VERSION 5.7 ;
  NOWIREEXTENSIONATPIN ON ;
  DIVIDERCHAR "/" ;
  BUSBITCHARS "[]" ;
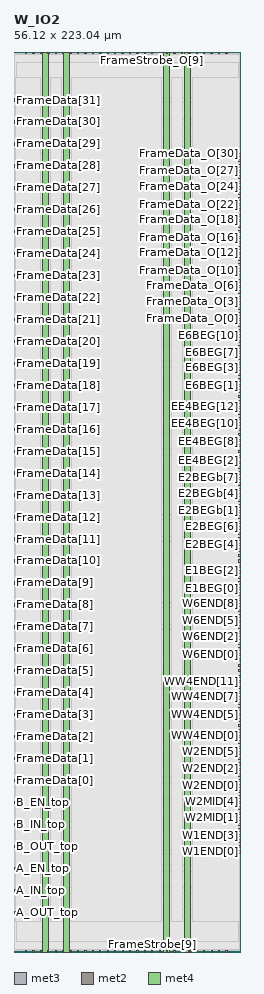
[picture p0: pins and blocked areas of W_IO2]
MACRO W_IO2
  CLASS BLOCK ;
  FOREIGN W_IO2 ;
  ORIGIN 0.000 0.000 ;
  SIZE 56.120 BY 223.040 ;
  PIN A_EN_top
    DIRECTION OUTPUT ;
    USE SIGNAL ;
    ANTENNADIFFAREA 0.702900 ;
    PORT
      LAYER met3 ;
        RECT 0.000 20.440 0.600 21.040 ;
    END
  END A_EN_top
  PIN A_IN_top
    DIRECTION OUTPUT ;
    USE SIGNAL ;
    ANTENNADIFFAREA 0.702900 ;
    PORT
      LAYER met3 ;
        RECT 0.000 15.000 0.600 15.600 ;
    END
  END A_IN_top
  PIN A_OUT_top
    DIRECTION INPUT ;
    USE SIGNAL ;
    ANTENNAGATEAREA 0.252000 ;
    PORT
      LAYER met3 ;
        RECT 0.000 9.560 0.600 10.160 ;
    END
  END A_OUT_top
  PIN B_EN_top
    DIRECTION OUTPUT ;
    USE SIGNAL ;
    ANTENNADIFFAREA 0.702900 ;
    PORT
      LAYER met3 ;
        RECT 0.000 36.760 0.600 37.360 ;
    END
  END B_EN_top
  PIN B_IN_top
    DIRECTION OUTPUT ;
    USE SIGNAL ;
    ANTENNADIFFAREA 0.702900 ;
    PORT
      LAYER met3 ;
        RECT 0.000 31.320 0.600 31.920 ;
    END
  END B_IN_top
  PIN B_OUT_top
    DIRECTION INPUT ;
    USE SIGNAL ;
    ANTENNAGATEAREA 0.252000 ;
    PORT
      LAYER met3 ;
        RECT 0.000 25.880 0.600 26.480 ;
    END
  END B_OUT_top
  PIN E1BEG[0]
    DIRECTION OUTPUT ;
    USE SIGNAL ;
    ANTENNADIFFAREA 0.702900 ;
    PORT
      LAYER met3 ;
        RECT 55.520 89.800 56.120 90.400 ;
    END
  END E1BEG[0]
  PIN E1BEG[1]
    DIRECTION OUTPUT ;
    USE SIGNAL ;
    ANTENNADIFFAREA 0.702900 ;
    PORT
      LAYER met3 ;
        RECT 55.520 91.160 56.120 91.760 ;
    END
  END E1BEG[1]
  PIN E1BEG[2]
    DIRECTION OUTPUT ;
    USE SIGNAL ;
    ANTENNADIFFAREA 0.702900 ;
    PORT
      LAYER met3 ;
        RECT 55.520 92.520 56.120 93.120 ;
    END
  END E1BEG[2]
  PIN E1BEG[3]
    DIRECTION OUTPUT ;
    USE SIGNAL ;
    ANTENNADIFFAREA 0.702900 ;
    PORT
      LAYER met3 ;
        RECT 55.520 93.880 56.120 94.480 ;
    END
  END E1BEG[3]
  PIN E2BEG[0]
    DIRECTION OUTPUT ;
    USE SIGNAL ;
    ANTENNADIFFAREA 0.702900 ;
    PORT
      LAYER met3 ;
        RECT 55.520 95.240 56.120 95.840 ;
    END
  END E2BEG[0]
  PIN E2BEG[1]
    DIRECTION OUTPUT ;
    USE SIGNAL ;
    ANTENNADIFFAREA 0.702900 ;
    PORT
      LAYER met3 ;
        RECT 55.520 96.600 56.120 97.200 ;
    END
  END E2BEG[1]
  PIN E2BEG[2]
    DIRECTION OUTPUT ;
    USE SIGNAL ;
    ANTENNADIFFAREA 0.702900 ;
    PORT
      LAYER met3 ;
        RECT 55.520 97.960 56.120 98.560 ;
    END
  END E2BEG[2]
  PIN E2BEG[3]
    DIRECTION OUTPUT ;
    USE SIGNAL ;
    ANTENNADIFFAREA 0.702900 ;
    PORT
      LAYER met3 ;
        RECT 55.520 99.320 56.120 99.920 ;
    END
  END E2BEG[3]
  PIN E2BEG[4]
    DIRECTION OUTPUT ;
    USE SIGNAL ;
    ANTENNADIFFAREA 0.702900 ;
    PORT
      LAYER met3 ;
        RECT 55.520 100.680 56.120 101.280 ;
    END
  END E2BEG[4]
  PIN E2BEG[5]
    DIRECTION OUTPUT ;
    USE SIGNAL ;
    ANTENNADIFFAREA 0.702900 ;
    PORT
      LAYER met3 ;
        RECT 55.520 102.040 56.120 102.640 ;
    END
  END E2BEG[5]
  PIN E2BEG[6]
    DIRECTION OUTPUT ;
    USE SIGNAL ;
    ANTENNADIFFAREA 0.702900 ;
    PORT
      LAYER met3 ;
        RECT 55.520 103.400 56.120 104.000 ;
    END
  END E2BEG[6]
  PIN E2BEG[7]
    DIRECTION OUTPUT ;
    USE SIGNAL ;
    ANTENNADIFFAREA 0.702900 ;
    PORT
      LAYER met3 ;
        RECT 55.520 104.760 56.120 105.360 ;
    END
  END E2BEG[7]
  PIN E2BEGb[0]
    DIRECTION OUTPUT ;
    USE SIGNAL ;
    ANTENNADIFFAREA 0.702900 ;
    PORT
      LAYER met3 ;
        RECT 55.520 106.120 56.120 106.720 ;
    END
  END E2BEGb[0]
  PIN E2BEGb[1]
    DIRECTION OUTPUT ;
    USE SIGNAL ;
    ANTENNADIFFAREA 0.702900 ;
    PORT
      LAYER met3 ;
        RECT 55.520 107.480 56.120 108.080 ;
    END
  END E2BEGb[1]
  PIN E2BEGb[2]
    DIRECTION OUTPUT ;
    USE SIGNAL ;
    ANTENNADIFFAREA 0.702900 ;
    PORT
      LAYER met3 ;
        RECT 55.520 108.840 56.120 109.440 ;
    END
  END E2BEGb[2]
  PIN E2BEGb[3]
    DIRECTION OUTPUT ;
    USE SIGNAL ;
    ANTENNADIFFAREA 0.702900 ;
    PORT
      LAYER met3 ;
        RECT 55.520 110.200 56.120 110.800 ;
    END
  END E2BEGb[3]
  PIN E2BEGb[4]
    DIRECTION OUTPUT ;
    USE SIGNAL ;
    ANTENNADIFFAREA 0.702900 ;
    PORT
      LAYER met3 ;
        RECT 55.520 111.560 56.120 112.160 ;
    END
  END E2BEGb[4]
  PIN E2BEGb[5]
    DIRECTION OUTPUT ;
    USE SIGNAL ;
    ANTENNADIFFAREA 0.702900 ;
    PORT
      LAYER met3 ;
        RECT 55.520 112.920 56.120 113.520 ;
    END
  END E2BEGb[5]
  PIN E2BEGb[6]
    DIRECTION OUTPUT ;
    USE SIGNAL ;
    ANTENNADIFFAREA 0.702900 ;
    PORT
      LAYER met3 ;
        RECT 55.520 114.280 56.120 114.880 ;
    END
  END E2BEGb[6]
  PIN E2BEGb[7]
    DIRECTION OUTPUT ;
    USE SIGNAL ;
    ANTENNADIFFAREA 0.702900 ;
    PORT
      LAYER met3 ;
        RECT 55.520 115.640 56.120 116.240 ;
    END
  END E2BEGb[7]
  PIN E6BEG[0]
    DIRECTION OUTPUT ;
    USE SIGNAL ;
    ANTENNADIFFAREA 0.702900 ;
    PORT
      LAYER met3 ;
        RECT 55.520 138.760 56.120 139.360 ;
    END
  END E6BEG[0]
  PIN E6BEG[10]
    DIRECTION OUTPUT ;
    USE SIGNAL ;
    ANTENNADIFFAREA 0.702900 ;
    PORT
      LAYER met3 ;
        RECT 55.520 152.360 56.120 152.960 ;
    END
  END E6BEG[10]
  PIN E6BEG[11]
    DIRECTION OUTPUT ;
    USE SIGNAL ;
    ANTENNADIFFAREA 0.702900 ;
    PORT
      LAYER met3 ;
        RECT 55.520 153.720 56.120 154.320 ;
    END
  END E6BEG[11]
  PIN E6BEG[1]
    DIRECTION OUTPUT ;
    USE SIGNAL ;
    ANTENNADIFFAREA 0.702900 ;
    PORT
      LAYER met3 ;
        RECT 55.520 140.120 56.120 140.720 ;
    END
  END E6BEG[1]
  PIN E6BEG[2]
    DIRECTION OUTPUT ;
    USE SIGNAL ;
    ANTENNADIFFAREA 0.702900 ;
    PORT
      LAYER met3 ;
        RECT 55.520 141.480 56.120 142.080 ;
    END
  END E6BEG[2]
  PIN E6BEG[3]
    DIRECTION OUTPUT ;
    USE SIGNAL ;
    ANTENNADIFFAREA 0.702900 ;
    PORT
      LAYER met3 ;
        RECT 55.520 142.840 56.120 143.440 ;
    END
  END E6BEG[3]
  PIN E6BEG[4]
    DIRECTION OUTPUT ;
    USE SIGNAL ;
    ANTENNADIFFAREA 0.702900 ;
    PORT
      LAYER met3 ;
        RECT 55.520 144.200 56.120 144.800 ;
    END
  END E6BEG[4]
  PIN E6BEG[5]
    DIRECTION OUTPUT ;
    USE SIGNAL ;
    ANTENNADIFFAREA 0.702900 ;
    PORT
      LAYER met3 ;
        RECT 55.520 145.560 56.120 146.160 ;
    END
  END E6BEG[5]
  PIN E6BEG[6]
    DIRECTION OUTPUT ;
    USE SIGNAL ;
    ANTENNADIFFAREA 0.702900 ;
    PORT
      LAYER met3 ;
        RECT 55.520 146.920 56.120 147.520 ;
    END
  END E6BEG[6]
  PIN E6BEG[7]
    DIRECTION OUTPUT ;
    USE SIGNAL ;
    ANTENNADIFFAREA 0.702900 ;
    PORT
      LAYER met3 ;
        RECT 55.520 148.280 56.120 148.880 ;
    END
  END E6BEG[7]
  PIN E6BEG[8]
    DIRECTION OUTPUT ;
    USE SIGNAL ;
    ANTENNADIFFAREA 0.702900 ;
    PORT
      LAYER met3 ;
        RECT 55.520 149.640 56.120 150.240 ;
    END
  END E6BEG[8]
  PIN E6BEG[9]
    DIRECTION OUTPUT ;
    USE SIGNAL ;
    ANTENNADIFFAREA 0.702900 ;
    PORT
      LAYER met3 ;
        RECT 55.520 151.000 56.120 151.600 ;
    END
  END E6BEG[9]
  PIN EE4BEG[0]
    DIRECTION OUTPUT ;
    USE SIGNAL ;
    ANTENNADIFFAREA 0.702900 ;
    PORT
      LAYER met3 ;
        RECT 55.520 117.000 56.120 117.600 ;
    END
  END EE4BEG[0]
  PIN EE4BEG[10]
    DIRECTION OUTPUT ;
    USE SIGNAL ;
    ANTENNADIFFAREA 0.702900 ;
    PORT
      LAYER met3 ;
        RECT 55.520 130.600 56.120 131.200 ;
    END
  END EE4BEG[10]
  PIN EE4BEG[11]
    DIRECTION OUTPUT ;
    USE SIGNAL ;
    ANTENNADIFFAREA 0.702900 ;
    PORT
      LAYER met3 ;
        RECT 55.520 131.960 56.120 132.560 ;
    END
  END EE4BEG[11]
  PIN EE4BEG[12]
    DIRECTION OUTPUT ;
    USE SIGNAL ;
    ANTENNADIFFAREA 0.702900 ;
    PORT
      LAYER met3 ;
        RECT 55.520 133.320 56.120 133.920 ;
    END
  END EE4BEG[12]
  PIN EE4BEG[13]
    DIRECTION OUTPUT ;
    USE SIGNAL ;
    ANTENNADIFFAREA 0.702900 ;
    PORT
      LAYER met3 ;
        RECT 55.520 134.680 56.120 135.280 ;
    END
  END EE4BEG[13]
  PIN EE4BEG[14]
    DIRECTION OUTPUT ;
    USE SIGNAL ;
    ANTENNADIFFAREA 0.702900 ;
    PORT
      LAYER met3 ;
        RECT 55.520 136.040 56.120 136.640 ;
    END
  END EE4BEG[14]
  PIN EE4BEG[15]
    DIRECTION OUTPUT ;
    USE SIGNAL ;
    ANTENNADIFFAREA 0.702900 ;
    PORT
      LAYER met3 ;
        RECT 55.520 137.400 56.120 138.000 ;
    END
  END EE4BEG[15]
  PIN EE4BEG[1]
    DIRECTION OUTPUT ;
    USE SIGNAL ;
    ANTENNADIFFAREA 0.702900 ;
    PORT
      LAYER met3 ;
        RECT 55.520 118.360 56.120 118.960 ;
    END
  END EE4BEG[1]
  PIN EE4BEG[2]
    DIRECTION OUTPUT ;
    USE SIGNAL ;
    ANTENNADIFFAREA 0.702900 ;
    PORT
      LAYER met3 ;
        RECT 55.520 119.720 56.120 120.320 ;
    END
  END EE4BEG[2]
  PIN EE4BEG[3]
    DIRECTION OUTPUT ;
    USE SIGNAL ;
    ANTENNADIFFAREA 0.702900 ;
    PORT
      LAYER met3 ;
        RECT 55.520 121.080 56.120 121.680 ;
    END
  END EE4BEG[3]
  PIN EE4BEG[4]
    DIRECTION OUTPUT ;
    USE SIGNAL ;
    ANTENNADIFFAREA 0.702900 ;
    PORT
      LAYER met3 ;
        RECT 55.520 122.440 56.120 123.040 ;
    END
  END EE4BEG[4]
  PIN EE4BEG[5]
    DIRECTION OUTPUT ;
    USE SIGNAL ;
    ANTENNADIFFAREA 0.702900 ;
    PORT
      LAYER met3 ;
        RECT 55.520 123.800 56.120 124.400 ;
    END
  END EE4BEG[5]
  PIN EE4BEG[6]
    DIRECTION OUTPUT ;
    USE SIGNAL ;
    ANTENNADIFFAREA 0.702900 ;
    PORT
      LAYER met3 ;
        RECT 55.520 125.160 56.120 125.760 ;
    END
  END EE4BEG[6]
  PIN EE4BEG[7]
    DIRECTION OUTPUT ;
    USE SIGNAL ;
    ANTENNADIFFAREA 0.702900 ;
    PORT
      LAYER met3 ;
        RECT 55.520 126.520 56.120 127.120 ;
    END
  END EE4BEG[7]
  PIN EE4BEG[8]
    DIRECTION OUTPUT ;
    USE SIGNAL ;
    ANTENNADIFFAREA 0.702900 ;
    PORT
      LAYER met3 ;
        RECT 55.520 127.880 56.120 128.480 ;
    END
  END EE4BEG[8]
  PIN EE4BEG[9]
    DIRECTION OUTPUT ;
    USE SIGNAL ;
    ANTENNADIFFAREA 0.702900 ;
    PORT
      LAYER met3 ;
        RECT 55.520 129.240 56.120 129.840 ;
    END
  END EE4BEG[9]
  PIN FrameData[0]
    DIRECTION INPUT ;
    USE SIGNAL ;
    ANTENNAGATEAREA 0.636000 ;
    PORT
      LAYER met3 ;
        RECT 0.000 42.200 0.600 42.800 ;
    END
  END FrameData[0]
  PIN FrameData[10]
    DIRECTION INPUT ;
    USE SIGNAL ;
    ANTENNAGATEAREA 0.795000 ;
    PORT
      LAYER met3 ;
        RECT 0.000 96.600 0.600 97.200 ;
    END
  END FrameData[10]
  PIN FrameData[11]
    DIRECTION INPUT ;
    USE SIGNAL ;
    ANTENNAGATEAREA 0.795000 ;
    PORT
      LAYER met3 ;
        RECT 0.000 102.040 0.600 102.640 ;
    END
  END FrameData[11]
  PIN FrameData[12]
    DIRECTION INPUT ;
    USE SIGNAL ;
    ANTENNAGATEAREA 0.795000 ;
    PORT
      LAYER met3 ;
        RECT 0.000 107.480 0.600 108.080 ;
    END
  END FrameData[12]
  PIN FrameData[13]
    DIRECTION INPUT ;
    USE SIGNAL ;
    ANTENNAGATEAREA 0.795000 ;
    PORT
      LAYER met3 ;
        RECT 0.000 112.920 0.600 113.520 ;
    END
  END FrameData[13]
  PIN FrameData[14]
    DIRECTION INPUT ;
    USE SIGNAL ;
    ANTENNAGATEAREA 0.795000 ;
    PORT
      LAYER met3 ;
        RECT 0.000 118.360 0.600 118.960 ;
    END
  END FrameData[14]
  PIN FrameData[15]
    DIRECTION INPUT ;
    USE SIGNAL ;
    ANTENNAGATEAREA 0.795000 ;
    PORT
      LAYER met3 ;
        RECT 0.000 123.800 0.600 124.400 ;
    END
  END FrameData[15]
  PIN FrameData[16]
    DIRECTION INPUT ;
    USE SIGNAL ;
    ANTENNAGATEAREA 0.795000 ;
    PORT
      LAYER met3 ;
        RECT 0.000 129.240 0.600 129.840 ;
    END
  END FrameData[16]
  PIN FrameData[17]
    DIRECTION INPUT ;
    USE SIGNAL ;
    ANTENNAGATEAREA 0.795000 ;
    PORT
      LAYER met3 ;
        RECT 0.000 134.680 0.600 135.280 ;
    END
  END FrameData[17]
  PIN FrameData[18]
    DIRECTION INPUT ;
    USE SIGNAL ;
    ANTENNAGATEAREA 1.229700 ;
    ANTENNADIFFAREA 0.434700 ;
    PORT
      LAYER met3 ;
        RECT 0.000 140.120 0.600 140.720 ;
    END
  END FrameData[18]
  PIN FrameData[19]
    DIRECTION INPUT ;
    USE SIGNAL ;
    ANTENNAGATEAREA 0.795000 ;
    PORT
      LAYER met3 ;
        RECT 0.000 145.560 0.600 146.160 ;
    END
  END FrameData[19]
  PIN FrameData[1]
    DIRECTION INPUT ;
    USE SIGNAL ;
    ANTENNAGATEAREA 0.636000 ;
    PORT
      LAYER met3 ;
        RECT 0.000 47.640 0.600 48.240 ;
    END
  END FrameData[1]
  PIN FrameData[20]
    DIRECTION INPUT ;
    USE SIGNAL ;
    ANTENNAGATEAREA 0.795000 ;
    PORT
      LAYER met3 ;
        RECT 0.000 151.000 0.600 151.600 ;
    END
  END FrameData[20]
  PIN FrameData[21]
    DIRECTION INPUT ;
    USE SIGNAL ;
    ANTENNAGATEAREA 0.795000 ;
    PORT
      LAYER met3 ;
        RECT 0.000 156.440 0.600 157.040 ;
    END
  END FrameData[21]
  PIN FrameData[22]
    DIRECTION INPUT ;
    USE SIGNAL ;
    ANTENNAGATEAREA 1.229700 ;
    ANTENNADIFFAREA 0.434700 ;
    PORT
      LAYER met3 ;
        RECT 0.000 161.880 0.600 162.480 ;
    END
  END FrameData[22]
  PIN FrameData[23]
    DIRECTION INPUT ;
    USE SIGNAL ;
    ANTENNAGATEAREA 0.795000 ;
    PORT
      LAYER met3 ;
        RECT 0.000 167.320 0.600 167.920 ;
    END
  END FrameData[23]
  PIN FrameData[24]
    DIRECTION INPUT ;
    USE SIGNAL ;
    ANTENNAGATEAREA 0.795000 ;
    PORT
      LAYER met3 ;
        RECT 0.000 172.760 0.600 173.360 ;
    END
  END FrameData[24]
  PIN FrameData[25]
    DIRECTION INPUT ;
    USE SIGNAL ;
    ANTENNAGATEAREA 0.795000 ;
    PORT
      LAYER met3 ;
        RECT 0.000 178.200 0.600 178.800 ;
    END
  END FrameData[25]
  PIN FrameData[26]
    DIRECTION INPUT ;
    USE SIGNAL ;
    ANTENNAGATEAREA 0.795000 ;
    PORT
      LAYER met3 ;
        RECT 0.000 183.640 0.600 184.240 ;
    END
  END FrameData[26]
  PIN FrameData[27]
    DIRECTION INPUT ;
    USE SIGNAL ;
    ANTENNAGATEAREA 0.795000 ;
    PORT
      LAYER met3 ;
        RECT 0.000 189.080 0.600 189.680 ;
    END
  END FrameData[27]
  PIN FrameData[28]
    DIRECTION INPUT ;
    USE SIGNAL ;
    ANTENNAGATEAREA 0.795000 ;
    PORT
      LAYER met3 ;
        RECT 0.000 194.520 0.600 195.120 ;
    END
  END FrameData[28]
  PIN FrameData[29]
    DIRECTION INPUT ;
    USE SIGNAL ;
    ANTENNAGATEAREA 0.795000 ;
    PORT
      LAYER met3 ;
        RECT 0.000 199.960 0.600 200.560 ;
    END
  END FrameData[29]
  PIN FrameData[2]
    DIRECTION INPUT ;
    USE SIGNAL ;
    ANTENNAGATEAREA 0.795000 ;
    PORT
      LAYER met3 ;
        RECT 0.000 53.080 0.600 53.680 ;
    END
  END FrameData[2]
  PIN FrameData[30]
    DIRECTION INPUT ;
    USE SIGNAL ;
    ANTENNAGATEAREA 0.795000 ;
    PORT
      LAYER met3 ;
        RECT 0.000 205.400 0.600 206.000 ;
    END
  END FrameData[30]
  PIN FrameData[31]
    DIRECTION INPUT ;
    USE SIGNAL ;
    ANTENNAGATEAREA 0.795000 ;
    PORT
      LAYER met3 ;
        RECT 0.000 210.840 0.600 211.440 ;
    END
  END FrameData[31]
  PIN FrameData[3]
    DIRECTION INPUT ;
    USE SIGNAL ;
    ANTENNAGATEAREA 0.795000 ;
    PORT
      LAYER met3 ;
        RECT 0.000 58.520 0.600 59.120 ;
    END
  END FrameData[3]
  PIN FrameData[4]
    DIRECTION INPUT ;
    USE SIGNAL ;
    ANTENNAGATEAREA 0.795000 ;
    PORT
      LAYER met3 ;
        RECT 0.000 63.960 0.600 64.560 ;
    END
  END FrameData[4]
  PIN FrameData[5]
    DIRECTION INPUT ;
    USE SIGNAL ;
    ANTENNAGATEAREA 0.795000 ;
    PORT
      LAYER met3 ;
        RECT 0.000 69.400 0.600 70.000 ;
    END
  END FrameData[5]
  PIN FrameData[6]
    DIRECTION INPUT ;
    USE SIGNAL ;
    ANTENNAGATEAREA 0.795000 ;
    PORT
      LAYER met3 ;
        RECT 0.000 74.840 0.600 75.440 ;
    END
  END FrameData[6]
  PIN FrameData[7]
    DIRECTION INPUT ;
    USE SIGNAL ;
    ANTENNAGATEAREA 0.795000 ;
    PORT
      LAYER met3 ;
        RECT 0.000 80.280 0.600 80.880 ;
    END
  END FrameData[7]
  PIN FrameData[8]
    DIRECTION INPUT ;
    USE SIGNAL ;
    ANTENNAGATEAREA 0.795000 ;
    PORT
      LAYER met3 ;
        RECT 0.000 85.720 0.600 86.320 ;
    END
  END FrameData[8]
  PIN FrameData[9]
    DIRECTION INPUT ;
    USE SIGNAL ;
    ANTENNAGATEAREA 0.795000 ;
    PORT
      LAYER met3 ;
        RECT 0.000 91.160 0.600 91.760 ;
    END
  END FrameData[9]
  PIN FrameData_O[0]
    DIRECTION OUTPUT ;
    USE SIGNAL ;
    ANTENNADIFFAREA 0.702900 ;
    PORT
      LAYER met3 ;
        RECT 55.520 155.080 56.120 155.680 ;
    END
  END FrameData_O[0]
  PIN FrameData_O[10]
    DIRECTION OUTPUT ;
    USE SIGNAL ;
    ANTENNADIFFAREA 0.702900 ;
    PORT
      LAYER met3 ;
        RECT 55.520 168.680 56.120 169.280 ;
    END
  END FrameData_O[10]
  PIN FrameData_O[11]
    DIRECTION OUTPUT ;
    USE SIGNAL ;
    ANTENNADIFFAREA 0.702900 ;
    PORT
      LAYER met3 ;
        RECT 55.520 170.040 56.120 170.640 ;
    END
  END FrameData_O[11]
  PIN FrameData_O[12]
    DIRECTION OUTPUT ;
    USE SIGNAL ;
    ANTENNADIFFAREA 0.702900 ;
    PORT
      LAYER met3 ;
        RECT 55.520 171.400 56.120 172.000 ;
    END
  END FrameData_O[12]
  PIN FrameData_O[13]
    DIRECTION OUTPUT ;
    USE SIGNAL ;
    ANTENNADIFFAREA 0.702900 ;
    PORT
      LAYER met3 ;
        RECT 55.520 172.760 56.120 173.360 ;
    END
  END FrameData_O[13]
  PIN FrameData_O[14]
    DIRECTION OUTPUT ;
    USE SIGNAL ;
    ANTENNADIFFAREA 0.702900 ;
    PORT
      LAYER met3 ;
        RECT 55.520 174.120 56.120 174.720 ;
    END
  END FrameData_O[14]
  PIN FrameData_O[15]
    DIRECTION OUTPUT ;
    USE SIGNAL ;
    ANTENNADIFFAREA 0.702900 ;
    PORT
      LAYER met3 ;
        RECT 55.520 175.480 56.120 176.080 ;
    END
  END FrameData_O[15]
  PIN FrameData_O[16]
    DIRECTION OUTPUT ;
    USE SIGNAL ;
    ANTENNADIFFAREA 0.702900 ;
    PORT
      LAYER met3 ;
        RECT 55.520 176.840 56.120 177.440 ;
    END
  END FrameData_O[16]
  PIN FrameData_O[17]
    DIRECTION OUTPUT ;
    USE SIGNAL ;
    ANTENNADIFFAREA 0.702900 ;
    PORT
      LAYER met3 ;
        RECT 55.520 178.200 56.120 178.800 ;
    END
  END FrameData_O[17]
  PIN FrameData_O[18]
    DIRECTION OUTPUT ;
    USE SIGNAL ;
    ANTENNADIFFAREA 0.702900 ;
    PORT
      LAYER met3 ;
        RECT 55.520 179.560 56.120 180.160 ;
    END
  END FrameData_O[18]
  PIN FrameData_O[19]
    DIRECTION OUTPUT ;
    USE SIGNAL ;
    ANTENNADIFFAREA 0.702900 ;
    PORT
      LAYER met3 ;
        RECT 55.520 180.920 56.120 181.520 ;
    END
  END FrameData_O[19]
  PIN FrameData_O[1]
    DIRECTION OUTPUT ;
    USE SIGNAL ;
    ANTENNADIFFAREA 0.702900 ;
    PORT
      LAYER met3 ;
        RECT 55.520 156.440 56.120 157.040 ;
    END
  END FrameData_O[1]
  PIN FrameData_O[20]
    DIRECTION OUTPUT ;
    USE SIGNAL ;
    ANTENNADIFFAREA 0.702900 ;
    PORT
      LAYER met3 ;
        RECT 55.520 182.280 56.120 182.880 ;
    END
  END FrameData_O[20]
  PIN FrameData_O[21]
    DIRECTION OUTPUT ;
    USE SIGNAL ;
    ANTENNADIFFAREA 0.702900 ;
    PORT
      LAYER met3 ;
        RECT 55.520 183.640 56.120 184.240 ;
    END
  END FrameData_O[21]
  PIN FrameData_O[22]
    DIRECTION OUTPUT ;
    USE SIGNAL ;
    ANTENNADIFFAREA 0.702900 ;
    PORT
      LAYER met3 ;
        RECT 55.520 185.000 56.120 185.600 ;
    END
  END FrameData_O[22]
  PIN FrameData_O[23]
    DIRECTION OUTPUT ;
    USE SIGNAL ;
    ANTENNADIFFAREA 0.702900 ;
    PORT
      LAYER met3 ;
        RECT 55.520 186.360 56.120 186.960 ;
    END
  END FrameData_O[23]
  PIN FrameData_O[24]
    DIRECTION OUTPUT ;
    USE SIGNAL ;
    ANTENNADIFFAREA 0.702900 ;
    PORT
      LAYER met3 ;
        RECT 55.520 187.720 56.120 188.320 ;
    END
  END FrameData_O[24]
  PIN FrameData_O[25]
    DIRECTION OUTPUT ;
    USE SIGNAL ;
    ANTENNADIFFAREA 0.702900 ;
    PORT
      LAYER met3 ;
        RECT 55.520 189.080 56.120 189.680 ;
    END
  END FrameData_O[25]
  PIN FrameData_O[26]
    DIRECTION OUTPUT ;
    USE SIGNAL ;
    ANTENNADIFFAREA 0.702900 ;
    PORT
      LAYER met3 ;
        RECT 55.520 190.440 56.120 191.040 ;
    END
  END FrameData_O[26]
  PIN FrameData_O[27]
    DIRECTION OUTPUT ;
    USE SIGNAL ;
    ANTENNADIFFAREA 0.702900 ;
    PORT
      LAYER met3 ;
        RECT 55.520 191.800 56.120 192.400 ;
    END
  END FrameData_O[27]
  PIN FrameData_O[28]
    DIRECTION OUTPUT ;
    USE SIGNAL ;
    ANTENNADIFFAREA 0.702900 ;
    PORT
      LAYER met3 ;
        RECT 55.520 193.160 56.120 193.760 ;
    END
  END FrameData_O[28]
  PIN FrameData_O[29]
    DIRECTION OUTPUT ;
    USE SIGNAL ;
    ANTENNADIFFAREA 0.702900 ;
    PORT
      LAYER met3 ;
        RECT 55.520 194.520 56.120 195.120 ;
    END
  END FrameData_O[29]
  PIN FrameData_O[2]
    DIRECTION OUTPUT ;
    USE SIGNAL ;
    ANTENNADIFFAREA 0.702900 ;
    PORT
      LAYER met3 ;
        RECT 55.520 157.800 56.120 158.400 ;
    END
  END FrameData_O[2]
  PIN FrameData_O[30]
    DIRECTION OUTPUT ;
    USE SIGNAL ;
    ANTENNADIFFAREA 0.702900 ;
    PORT
      LAYER met3 ;
        RECT 55.520 195.880 56.120 196.480 ;
    END
  END FrameData_O[30]
  PIN FrameData_O[31]
    DIRECTION OUTPUT ;
    USE SIGNAL ;
    ANTENNADIFFAREA 0.702900 ;
    PORT
      LAYER met3 ;
        RECT 55.520 197.240 56.120 197.840 ;
    END
  END FrameData_O[31]
  PIN FrameData_O[3]
    DIRECTION OUTPUT ;
    USE SIGNAL ;
    ANTENNADIFFAREA 0.702900 ;
    PORT
      LAYER met3 ;
        RECT 55.520 159.160 56.120 159.760 ;
    END
  END FrameData_O[3]
  PIN FrameData_O[4]
    DIRECTION OUTPUT ;
    USE SIGNAL ;
    ANTENNADIFFAREA 0.702900 ;
    PORT
      LAYER met3 ;
        RECT 55.520 160.520 56.120 161.120 ;
    END
  END FrameData_O[4]
  PIN FrameData_O[5]
    DIRECTION OUTPUT ;
    USE SIGNAL ;
    ANTENNADIFFAREA 0.702900 ;
    PORT
      LAYER met3 ;
        RECT 55.520 161.880 56.120 162.480 ;
    END
  END FrameData_O[5]
  PIN FrameData_O[6]
    DIRECTION OUTPUT ;
    USE SIGNAL ;
    ANTENNADIFFAREA 0.702900 ;
    PORT
      LAYER met3 ;
        RECT 55.520 163.240 56.120 163.840 ;
    END
  END FrameData_O[6]
  PIN FrameData_O[7]
    DIRECTION OUTPUT ;
    USE SIGNAL ;
    ANTENNADIFFAREA 0.702900 ;
    PORT
      LAYER met3 ;
        RECT 55.520 164.600 56.120 165.200 ;
    END
  END FrameData_O[7]
  PIN FrameData_O[8]
    DIRECTION OUTPUT ;
    USE SIGNAL ;
    ANTENNADIFFAREA 0.702900 ;
    PORT
      LAYER met3 ;
        RECT 55.520 165.960 56.120 166.560 ;
    END
  END FrameData_O[8]
  PIN FrameData_O[9]
    DIRECTION OUTPUT ;
    USE SIGNAL ;
    ANTENNADIFFAREA 0.702900 ;
    PORT
      LAYER met3 ;
        RECT 55.520 167.320 56.120 167.920 ;
    END
  END FrameData_O[9]
  PIN FrameStrobe[0]
    DIRECTION INPUT ;
    USE SIGNAL ;
    ANTENNAGATEAREA 5.247000 ;
    PORT
      LAYER met2 ;
        RECT 17.570 0.000 17.850 0.280 ;
    END
  END FrameStrobe[0]
  PIN FrameStrobe[10]
    DIRECTION INPUT ;
    USE SIGNAL ;
    ANTENNAGATEAREA 0.159000 ;
    PORT
      LAYER met2 ;
        RECT 35.970 0.000 36.250 0.280 ;
    END
  END FrameStrobe[10]
  PIN FrameStrobe[11]
    DIRECTION INPUT ;
    USE SIGNAL ;
    ANTENNAGATEAREA 0.159000 ;
    PORT
      LAYER met2 ;
        RECT 37.810 0.000 38.090 0.280 ;
    END
  END FrameStrobe[11]
  PIN FrameStrobe[12]
    DIRECTION INPUT ;
    USE SIGNAL ;
    ANTENNAGATEAREA 0.159000 ;
    PORT
      LAYER met2 ;
        RECT 39.650 0.000 39.930 0.280 ;
    END
  END FrameStrobe[12]
  PIN FrameStrobe[13]
    DIRECTION INPUT ;
    USE SIGNAL ;
    ANTENNAGATEAREA 0.159000 ;
    PORT
      LAYER met2 ;
        RECT 41.490 0.000 41.770 0.280 ;
    END
  END FrameStrobe[13]
  PIN FrameStrobe[14]
    DIRECTION INPUT ;
    USE SIGNAL ;
    ANTENNAGATEAREA 0.159000 ;
    PORT
      LAYER met2 ;
        RECT 43.330 0.000 43.610 0.280 ;
    END
  END FrameStrobe[14]
  PIN FrameStrobe[15]
    DIRECTION INPUT ;
    USE SIGNAL ;
    ANTENNAGATEAREA 0.159000 ;
    PORT
      LAYER met2 ;
        RECT 45.170 0.000 45.450 0.280 ;
    END
  END FrameStrobe[15]
  PIN FrameStrobe[16]
    DIRECTION INPUT ;
    USE SIGNAL ;
    ANTENNAGATEAREA 0.159000 ;
    PORT
      LAYER met2 ;
        RECT 47.010 0.000 47.290 0.280 ;
    END
  END FrameStrobe[16]
  PIN FrameStrobe[17]
    DIRECTION INPUT ;
    USE SIGNAL ;
    ANTENNAGATEAREA 0.159000 ;
    PORT
      LAYER met2 ;
        RECT 48.850 0.000 49.130 0.280 ;
    END
  END FrameStrobe[17]
  PIN FrameStrobe[18]
    DIRECTION INPUT ;
    USE SIGNAL ;
    ANTENNAGATEAREA 0.159000 ;
    PORT
      LAYER met2 ;
        RECT 50.690 0.000 50.970 0.280 ;
    END
  END FrameStrobe[18]
  PIN FrameStrobe[19]
    DIRECTION INPUT ;
    USE SIGNAL ;
    ANTENNAGATEAREA 0.159000 ;
    PORT
      LAYER met2 ;
        RECT 52.530 0.000 52.810 0.280 ;
    END
  END FrameStrobe[19]
  PIN FrameStrobe[1]
    DIRECTION INPUT ;
    USE SIGNAL ;
    ANTENNAGATEAREA 5.247000 ;
    PORT
      LAYER met2 ;
        RECT 19.410 0.000 19.690 0.280 ;
    END
  END FrameStrobe[1]
  PIN FrameStrobe[2]
    DIRECTION INPUT ;
    USE SIGNAL ;
    ANTENNAGATEAREA 5.247000 ;
    PORT
      LAYER met2 ;
        RECT 21.250 0.000 21.530 0.280 ;
    END
  END FrameStrobe[2]
  PIN FrameStrobe[3]
    DIRECTION INPUT ;
    USE SIGNAL ;
    ANTENNAGATEAREA 4.929000 ;
    PORT
      LAYER met2 ;
        RECT 23.090 0.000 23.370 0.280 ;
    END
  END FrameStrobe[3]
  PIN FrameStrobe[4]
    DIRECTION INPUT ;
    USE SIGNAL ;
    ANTENNAGATEAREA 0.159000 ;
    PORT
      LAYER met2 ;
        RECT 24.930 0.000 25.210 0.280 ;
    END
  END FrameStrobe[4]
  PIN FrameStrobe[5]
    DIRECTION INPUT ;
    USE SIGNAL ;
    ANTENNAGATEAREA 0.159000 ;
    PORT
      LAYER met2 ;
        RECT 26.770 0.000 27.050 0.280 ;
    END
  END FrameStrobe[5]
  PIN FrameStrobe[6]
    DIRECTION INPUT ;
    USE SIGNAL ;
    ANTENNAGATEAREA 0.159000 ;
    PORT
      LAYER met2 ;
        RECT 28.610 0.000 28.890 0.280 ;
    END
  END FrameStrobe[6]
  PIN FrameStrobe[7]
    DIRECTION INPUT ;
    USE SIGNAL ;
    ANTENNAGATEAREA 0.159000 ;
    PORT
      LAYER met2 ;
        RECT 30.450 0.000 30.730 0.280 ;
    END
  END FrameStrobe[7]
  PIN FrameStrobe[8]
    DIRECTION INPUT ;
    USE SIGNAL ;
    ANTENNAGATEAREA 0.159000 ;
    PORT
      LAYER met2 ;
        RECT 32.290 0.000 32.570 0.280 ;
    END
  END FrameStrobe[8]
  PIN FrameStrobe[9]
    DIRECTION INPUT ;
    USE SIGNAL ;
    ANTENNAGATEAREA 0.159000 ;
    PORT
      LAYER met2 ;
        RECT 34.130 0.000 34.410 0.280 ;
    END
  END FrameStrobe[9]
  PIN FrameStrobe_O[0]
    DIRECTION OUTPUT ;
    USE SIGNAL ;
    ANTENNADIFFAREA 0.702900 ;
    PORT
      LAYER met2 ;
        RECT 17.570 222.760 17.850 223.040 ;
    END
  END FrameStrobe_O[0]
  PIN FrameStrobe_O[10]
    DIRECTION OUTPUT ;
    USE SIGNAL ;
    ANTENNADIFFAREA 0.702900 ;
    PORT
      LAYER met2 ;
        RECT 35.970 222.760 36.250 223.040 ;
    END
  END FrameStrobe_O[10]
  PIN FrameStrobe_O[11]
    DIRECTION OUTPUT ;
    USE SIGNAL ;
    ANTENNADIFFAREA 0.702900 ;
    PORT
      LAYER met2 ;
        RECT 37.810 222.760 38.090 223.040 ;
    END
  END FrameStrobe_O[11]
  PIN FrameStrobe_O[12]
    DIRECTION OUTPUT ;
    USE SIGNAL ;
    ANTENNADIFFAREA 0.702900 ;
    PORT
      LAYER met2 ;
        RECT 39.650 222.760 39.930 223.040 ;
    END
  END FrameStrobe_O[12]
  PIN FrameStrobe_O[13]
    DIRECTION OUTPUT ;
    USE SIGNAL ;
    ANTENNADIFFAREA 0.702900 ;
    PORT
      LAYER met2 ;
        RECT 41.490 222.760 41.770 223.040 ;
    END
  END FrameStrobe_O[13]
  PIN FrameStrobe_O[14]
    DIRECTION OUTPUT ;
    USE SIGNAL ;
    ANTENNADIFFAREA 0.702900 ;
    PORT
      LAYER met2 ;
        RECT 43.330 222.760 43.610 223.040 ;
    END
  END FrameStrobe_O[14]
  PIN FrameStrobe_O[15]
    DIRECTION OUTPUT ;
    USE SIGNAL ;
    ANTENNADIFFAREA 0.702900 ;
    PORT
      LAYER met2 ;
        RECT 45.170 222.760 45.450 223.040 ;
    END
  END FrameStrobe_O[15]
  PIN FrameStrobe_O[16]
    DIRECTION OUTPUT ;
    USE SIGNAL ;
    ANTENNADIFFAREA 0.702900 ;
    PORT
      LAYER met2 ;
        RECT 47.010 222.760 47.290 223.040 ;
    END
  END FrameStrobe_O[16]
  PIN FrameStrobe_O[17]
    DIRECTION OUTPUT ;
    USE SIGNAL ;
    ANTENNADIFFAREA 0.702900 ;
    PORT
      LAYER met2 ;
        RECT 48.850 222.760 49.130 223.040 ;
    END
  END FrameStrobe_O[17]
  PIN FrameStrobe_O[18]
    DIRECTION OUTPUT ;
    USE SIGNAL ;
    ANTENNADIFFAREA 0.702900 ;
    PORT
      LAYER met2 ;
        RECT 50.690 222.760 50.970 223.040 ;
    END
  END FrameStrobe_O[18]
  PIN FrameStrobe_O[19]
    DIRECTION OUTPUT ;
    USE SIGNAL ;
    ANTENNADIFFAREA 0.702900 ;
    PORT
      LAYER met2 ;
        RECT 52.530 222.760 52.810 223.040 ;
    END
  END FrameStrobe_O[19]
  PIN FrameStrobe_O[1]
    DIRECTION OUTPUT ;
    USE SIGNAL ;
    ANTENNADIFFAREA 0.702900 ;
    PORT
      LAYER met2 ;
        RECT 19.410 222.760 19.690 223.040 ;
    END
  END FrameStrobe_O[1]
  PIN FrameStrobe_O[2]
    DIRECTION OUTPUT ;
    USE SIGNAL ;
    ANTENNADIFFAREA 0.702900 ;
    PORT
      LAYER met2 ;
        RECT 21.250 222.760 21.530 223.040 ;
    END
  END FrameStrobe_O[2]
  PIN FrameStrobe_O[3]
    DIRECTION OUTPUT ;
    USE SIGNAL ;
    ANTENNADIFFAREA 0.702900 ;
    PORT
      LAYER met2 ;
        RECT 23.090 222.760 23.370 223.040 ;
    END
  END FrameStrobe_O[3]
  PIN FrameStrobe_O[4]
    DIRECTION OUTPUT ;
    USE SIGNAL ;
    ANTENNADIFFAREA 0.702900 ;
    PORT
      LAYER met2 ;
        RECT 24.930 222.760 25.210 223.040 ;
    END
  END FrameStrobe_O[4]
  PIN FrameStrobe_O[5]
    DIRECTION OUTPUT ;
    USE SIGNAL ;
    ANTENNADIFFAREA 0.702900 ;
    PORT
      LAYER met2 ;
        RECT 26.770 222.760 27.050 223.040 ;
    END
  END FrameStrobe_O[5]
  PIN FrameStrobe_O[6]
    DIRECTION OUTPUT ;
    USE SIGNAL ;
    ANTENNADIFFAREA 0.702900 ;
    PORT
      LAYER met2 ;
        RECT 28.610 222.760 28.890 223.040 ;
    END
  END FrameStrobe_O[6]
  PIN FrameStrobe_O[7]
    DIRECTION OUTPUT ;
    USE SIGNAL ;
    ANTENNADIFFAREA 0.702900 ;
    PORT
      LAYER met2 ;
        RECT 30.450 222.760 30.730 223.040 ;
    END
  END FrameStrobe_O[7]
  PIN FrameStrobe_O[8]
    DIRECTION OUTPUT ;
    USE SIGNAL ;
    ANTENNADIFFAREA 0.702900 ;
    PORT
      LAYER met2 ;
        RECT 32.290 222.760 32.570 223.040 ;
    END
  END FrameStrobe_O[8]
  PIN FrameStrobe_O[9]
    DIRECTION OUTPUT ;
    USE SIGNAL ;
    ANTENNADIFFAREA 0.702900 ;
    PORT
      LAYER met2 ;
        RECT 34.130 222.760 34.410 223.040 ;
    END
  END FrameStrobe_O[9]
  PIN N_GBUF_BEG[0]
    DIRECTION OUTPUT ;
    USE SIGNAL ;
    ANTENNADIFFAREA 0.702900 ;
    PORT
      LAYER met2 ;
        RECT 2.850 222.760 3.130 223.040 ;
    END
  END N_GBUF_BEG[0]
  PIN N_GBUF_BEG[1]
    DIRECTION OUTPUT ;
    USE SIGNAL ;
    ANTENNADIFFAREA 0.702900 ;
    PORT
      LAYER met2 ;
        RECT 4.690 222.760 4.970 223.040 ;
    END
  END N_GBUF_BEG[1]
  PIN N_GBUF_BEG[2]
    DIRECTION OUTPUT ;
    USE SIGNAL ;
    ANTENNADIFFAREA 0.702900 ;
    PORT
      LAYER met2 ;
        RECT 6.530 222.760 6.810 223.040 ;
    END
  END N_GBUF_BEG[2]
  PIN N_GBUF_BEG[3]
    DIRECTION OUTPUT ;
    USE SIGNAL ;
    ANTENNADIFFAREA 0.702900 ;
    PORT
      LAYER met2 ;
        RECT 8.370 222.760 8.650 223.040 ;
    END
  END N_GBUF_BEG[3]
  PIN N_GBUF_END[0]
    DIRECTION INPUT ;
    USE SIGNAL ;
    ANTENNAGATEAREA 0.852000 ;
    PORT
      LAYER met2 ;
        RECT 2.850 0.000 3.130 0.280 ;
    END
  END N_GBUF_END[0]
  PIN N_GBUF_END[1]
    DIRECTION INPUT ;
    USE SIGNAL ;
    ANTENNAGATEAREA 0.477000 ;
    PORT
      LAYER met2 ;
        RECT 4.690 0.000 4.970 0.280 ;
    END
  END N_GBUF_END[1]
  PIN N_GBUF_END[2]
    DIRECTION INPUT ;
    USE SIGNAL ;
    ANTENNAGATEAREA 0.477000 ;
    PORT
      LAYER met2 ;
        RECT 6.530 0.000 6.810 0.280 ;
    END
  END N_GBUF_END[2]
  PIN N_GBUF_END[3]
    DIRECTION INPUT ;
    USE SIGNAL ;
    ANTENNAGATEAREA 1.781100 ;
    ANTENNADIFFAREA 1.304100 ;
    PORT
      LAYER met2 ;
        RECT 8.370 0.000 8.650 0.280 ;
    END
  END N_GBUF_END[3]
  PIN S_GBUF_FEED_BEG[0]
    DIRECTION OUTPUT ;
    USE SIGNAL ;
    ANTENNADIFFAREA 0.702900 ;
    PORT
      LAYER met2 ;
        RECT 10.210 0.000 10.490 0.280 ;
    END
  END S_GBUF_FEED_BEG[0]
  PIN S_GBUF_FEED_BEG[1]
    DIRECTION OUTPUT ;
    USE SIGNAL ;
    ANTENNADIFFAREA 0.702900 ;
    PORT
      LAYER met2 ;
        RECT 12.050 0.000 12.330 0.280 ;
    END
  END S_GBUF_FEED_BEG[1]
  PIN S_GBUF_FEED_BEG[2]
    DIRECTION OUTPUT ;
    USE SIGNAL ;
    ANTENNADIFFAREA 0.702900 ;
    PORT
      LAYER met2 ;
        RECT 13.890 0.000 14.170 0.280 ;
    END
  END S_GBUF_FEED_BEG[2]
  PIN S_GBUF_FEED_BEG[3]
    DIRECTION OUTPUT ;
    USE SIGNAL ;
    ANTENNADIFFAREA 0.702900 ;
    PORT
      LAYER met2 ;
        RECT 15.730 0.000 16.010 0.280 ;
    END
  END S_GBUF_FEED_BEG[3]
  PIN S_GBUF_FEED_END[0]
    DIRECTION INPUT ;
    USE SIGNAL ;
    ANTENNAGATEAREA 0.593700 ;
    ANTENNADIFFAREA 0.434700 ;
    PORT
      LAYER met2 ;
        RECT 10.210 222.760 10.490 223.040 ;
    END
  END S_GBUF_FEED_END[0]
  PIN S_GBUF_FEED_END[1]
    DIRECTION INPUT ;
    USE SIGNAL ;
    ANTENNAGATEAREA 0.159000 ;
    PORT
      LAYER met2 ;
        RECT 12.050 222.760 12.330 223.040 ;
    END
  END S_GBUF_FEED_END[1]
  PIN S_GBUF_FEED_END[2]
    DIRECTION INPUT ;
    USE SIGNAL ;
    ANTENNAGATEAREA 0.159000 ;
    PORT
      LAYER met2 ;
        RECT 13.890 222.760 14.170 223.040 ;
    END
  END S_GBUF_FEED_END[2]
  PIN S_GBUF_FEED_END[3]
    DIRECTION INPUT ;
    USE SIGNAL ;
    ANTENNAGATEAREA 0.593700 ;
    ANTENNADIFFAREA 0.434700 ;
    PORT
      LAYER met2 ;
        RECT 15.730 222.760 16.010 223.040 ;
    END
  END S_GBUF_FEED_END[3]
  PIN VGND
    DIRECTION INOUT ;
    USE GROUND ;
    PORT
      LAYER met4 ;
        RECT 12.260 0.000 13.860 223.040 ;
    END
    PORT
      LAYER met4 ;
        RECT 42.260 0.000 43.860 223.040 ;
    END
  END VGND
  PIN VPWR
    DIRECTION INOUT ;
    USE POWER ;
    PORT
      LAYER met4 ;
        RECT 6.960 0.000 8.560 223.040 ;
    END
    PORT
      LAYER met4 ;
        RECT 36.960 0.000 38.560 223.040 ;
    END
  END VPWR
  PIN W1END[0]
    DIRECTION INPUT ;
    USE SIGNAL ;
    ANTENNAGATEAREA 0.855000 ;
    PORT
      LAYER met3 ;
        RECT 55.520 24.520 56.120 25.120 ;
    END
  END W1END[0]
  PIN W1END[1]
    DIRECTION INPUT ;
    USE SIGNAL ;
    ANTENNAGATEAREA 1.289700 ;
    ANTENNADIFFAREA 0.434700 ;
    PORT
      LAYER met3 ;
        RECT 55.520 25.880 56.120 26.480 ;
    END
  END W1END[1]
  PIN W1END[2]
    DIRECTION INPUT ;
    USE SIGNAL ;
    ANTENNAGATEAREA 0.603000 ;
    PORT
      LAYER met3 ;
        RECT 55.520 27.240 56.120 27.840 ;
    END
  END W1END[2]
  PIN W1END[3]
    DIRECTION INPUT ;
    USE SIGNAL ;
    ANTENNAGATEAREA 0.603000 ;
    PORT
      LAYER met3 ;
        RECT 55.520 28.600 56.120 29.200 ;
    END
  END W1END[3]
  PIN W2END[0]
    DIRECTION INPUT ;
    USE SIGNAL ;
    ANTENNAGATEAREA 0.813000 ;
    PORT
      LAYER met3 ;
        RECT 55.520 40.840 56.120 41.440 ;
    END
  END W2END[0]
  PIN W2END[1]
    DIRECTION INPUT ;
    USE SIGNAL ;
    ANTENNAGATEAREA 0.813000 ;
    PORT
      LAYER met3 ;
        RECT 55.520 42.200 56.120 42.800 ;
    END
  END W2END[1]
  PIN W2END[2]
    DIRECTION INPUT ;
    USE SIGNAL ;
    ANTENNAGATEAREA 0.318000 ;
    PORT
      LAYER met3 ;
        RECT 55.520 43.560 56.120 44.160 ;
    END
  END W2END[2]
  PIN W2END[3]
    DIRECTION INPUT ;
    USE SIGNAL ;
    ANTENNAGATEAREA 0.318000 ;
    PORT
      LAYER met3 ;
        RECT 55.520 44.920 56.120 45.520 ;
    END
  END W2END[3]
  PIN W2END[4]
    DIRECTION INPUT ;
    USE SIGNAL ;
    ANTENNAGATEAREA 0.729000 ;
    PORT
      LAYER met3 ;
        RECT 55.520 46.280 56.120 46.880 ;
    END
  END W2END[4]
  PIN W2END[5]
    DIRECTION INPUT ;
    USE SIGNAL ;
    ANTENNAGATEAREA 0.729000 ;
    PORT
      LAYER met3 ;
        RECT 55.520 47.640 56.120 48.240 ;
    END
  END W2END[5]
  PIN W2END[6]
    DIRECTION INPUT ;
    USE SIGNAL ;
    ANTENNAGATEAREA 0.911700 ;
    ANTENNADIFFAREA 0.434700 ;
    PORT
      LAYER met3 ;
        RECT 55.520 49.000 56.120 49.600 ;
    END
  END W2END[6]
  PIN W2END[7]
    DIRECTION INPUT ;
    USE SIGNAL ;
    ANTENNAGATEAREA 0.477000 ;
    PORT
      LAYER met3 ;
        RECT 55.520 50.360 56.120 50.960 ;
    END
  END W2END[7]
  PIN W2MID[0]
    DIRECTION INPUT ;
    USE SIGNAL ;
    ANTENNAGATEAREA 0.603000 ;
    PORT
      LAYER met3 ;
        RECT 55.520 29.960 56.120 30.560 ;
    END
  END W2MID[0]
  PIN W2MID[1]
    DIRECTION INPUT ;
    USE SIGNAL ;
    ANTENNAGATEAREA 0.603000 ;
    PORT
      LAYER met3 ;
        RECT 55.520 31.320 56.120 31.920 ;
    END
  END W2MID[1]
  PIN W2MID[2]
    DIRECTION INPUT ;
    USE SIGNAL ;
    ANTENNAGATEAREA 0.477000 ;
    PORT
      LAYER met3 ;
        RECT 55.520 32.680 56.120 33.280 ;
    END
  END W2MID[2]
  PIN W2MID[3]
    DIRECTION INPUT ;
    USE SIGNAL ;
    ANTENNAGATEAREA 0.477000 ;
    PORT
      LAYER met3 ;
        RECT 55.520 34.040 56.120 34.640 ;
    END
  END W2MID[3]
  PIN W2MID[4]
    DIRECTION INPUT ;
    USE SIGNAL ;
    ANTENNAGATEAREA 0.603000 ;
    PORT
      LAYER met3 ;
        RECT 55.520 35.400 56.120 36.000 ;
    END
  END W2MID[4]
  PIN W2MID[5]
    DIRECTION INPUT ;
    USE SIGNAL ;
    ANTENNAGATEAREA 0.603000 ;
    PORT
      LAYER met3 ;
        RECT 55.520 36.760 56.120 37.360 ;
    END
  END W2MID[5]
  PIN W2MID[6]
    DIRECTION INPUT ;
    USE SIGNAL ;
    ANTENNAGATEAREA 0.477000 ;
    PORT
      LAYER met3 ;
        RECT 55.520 38.120 56.120 38.720 ;
    END
  END W2MID[6]
  PIN W2MID[7]
    DIRECTION INPUT ;
    USE SIGNAL ;
    ANTENNAGATEAREA 0.477000 ;
    PORT
      LAYER met3 ;
        RECT 55.520 39.480 56.120 40.080 ;
    END
  END W2MID[7]
  PIN W6END[0]
    DIRECTION INPUT ;
    USE SIGNAL ;
    ANTENNAGATEAREA 0.921000 ;
    PORT
      LAYER met3 ;
        RECT 55.520 73.480 56.120 74.080 ;
    END
  END W6END[0]
  PIN W6END[10]
    DIRECTION INPUT ;
    USE SIGNAL ;
    ANTENNAGATEAREA 0.636000 ;
    PORT
      LAYER met3 ;
        RECT 55.520 87.080 56.120 87.680 ;
    END
  END W6END[10]
  PIN W6END[11]
    DIRECTION INPUT ;
    USE SIGNAL ;
    ANTENNAGATEAREA 0.477000 ;
    PORT
      LAYER met3 ;
        RECT 55.520 88.440 56.120 89.040 ;
    END
  END W6END[11]
  PIN W6END[1]
    DIRECTION INPUT ;
    USE SIGNAL ;
    ANTENNAGATEAREA 1.080000 ;
    PORT
      LAYER met3 ;
        RECT 55.520 74.840 56.120 75.440 ;
    END
  END W6END[1]
  PIN W6END[2]
    DIRECTION INPUT ;
    USE SIGNAL ;
    ANTENNAGATEAREA 0.795000 ;
    PORT
      LAYER met3 ;
        RECT 55.520 76.200 56.120 76.800 ;
    END
  END W6END[2]
  PIN W6END[3]
    DIRECTION INPUT ;
    USE SIGNAL ;
    ANTENNAGATEAREA 0.954000 ;
    PORT
      LAYER met3 ;
        RECT 55.520 77.560 56.120 78.160 ;
    END
  END W6END[3]
  PIN W6END[4]
    DIRECTION INPUT ;
    USE SIGNAL ;
    ANTENNAGATEAREA 1.080000 ;
    PORT
      LAYER met3 ;
        RECT 55.520 78.920 56.120 79.520 ;
    END
  END W6END[4]
  PIN W6END[5]
    DIRECTION INPUT ;
    USE SIGNAL ;
    ANTENNAGATEAREA 1.080000 ;
    PORT
      LAYER met3 ;
        RECT 55.520 80.280 56.120 80.880 ;
    END
  END W6END[5]
  PIN W6END[6]
    DIRECTION INPUT ;
    USE SIGNAL ;
    ANTENNAGATEAREA 0.954000 ;
    PORT
      LAYER met3 ;
        RECT 55.520 81.640 56.120 82.240 ;
    END
  END W6END[6]
  PIN W6END[7]
    DIRECTION INPUT ;
    USE SIGNAL ;
    ANTENNAGATEAREA 0.954000 ;
    PORT
      LAYER met3 ;
        RECT 55.520 83.000 56.120 83.600 ;
    END
  END W6END[7]
  PIN W6END[8]
    DIRECTION INPUT ;
    USE SIGNAL ;
    ANTENNAGATEAREA 0.636000 ;
    PORT
      LAYER met3 ;
        RECT 55.520 84.360 56.120 84.960 ;
    END
  END W6END[8]
  PIN W6END[9]
    DIRECTION INPUT ;
    USE SIGNAL ;
    ANTENNAGATEAREA 0.477000 ;
    PORT
      LAYER met3 ;
        RECT 55.520 85.720 56.120 86.320 ;
    END
  END W6END[9]
  PIN WW4END[0]
    DIRECTION INPUT ;
    USE SIGNAL ;
    ANTENNAGATEAREA 0.972000 ;
    PORT
      LAYER met3 ;
        RECT 55.520 51.720 56.120 52.320 ;
    END
  END WW4END[0]
  PIN WW4END[10]
    DIRECTION INPUT ;
    USE SIGNAL ;
    ANTENNAGATEAREA 0.477000 ;
    PORT
      LAYER met3 ;
        RECT 55.520 65.320 56.120 65.920 ;
    END
  END WW4END[10]
  PIN WW4END[11]
    DIRECTION INPUT ;
    USE SIGNAL ;
    ANTENNAGATEAREA 0.477000 ;
    PORT
      LAYER met3 ;
        RECT 55.520 66.680 56.120 67.280 ;
    END
  END WW4END[11]
  PIN WW4END[12]
    DIRECTION INPUT ;
    USE SIGNAL ;
    ANTENNAGATEAREA 0.477000 ;
    PORT
      LAYER met3 ;
        RECT 55.520 68.040 56.120 68.640 ;
    END
  END WW4END[12]
  PIN WW4END[13]
    DIRECTION INPUT ;
    USE SIGNAL ;
    ANTENNAGATEAREA 0.477000 ;
    PORT
      LAYER met3 ;
        RECT 55.520 69.400 56.120 70.000 ;
    END
  END WW4END[13]
  PIN WW4END[14]
    DIRECTION INPUT ;
    USE SIGNAL ;
    ANTENNAGATEAREA 0.477000 ;
    PORT
      LAYER met3 ;
        RECT 55.520 70.760 56.120 71.360 ;
    END
  END WW4END[14]
  PIN WW4END[15]
    DIRECTION INPUT ;
    USE SIGNAL ;
    ANTENNAGATEAREA 0.477000 ;
    PORT
      LAYER met3 ;
        RECT 55.520 72.120 56.120 72.720 ;
    END
  END WW4END[15]
  PIN WW4END[1]
    DIRECTION INPUT ;
    USE SIGNAL ;
    ANTENNAGATEAREA 0.972000 ;
    PORT
      LAYER met3 ;
        RECT 55.520 53.080 56.120 53.680 ;
    END
  END WW4END[1]
  PIN WW4END[2]
    DIRECTION INPUT ;
    USE SIGNAL ;
    ANTENNAGATEAREA 0.477000 ;
    PORT
      LAYER met3 ;
        RECT 55.520 54.440 56.120 55.040 ;
    END
  END WW4END[2]
  PIN WW4END[3]
    DIRECTION INPUT ;
    USE SIGNAL ;
    ANTENNAGATEAREA 0.477000 ;
    PORT
      LAYER met3 ;
        RECT 55.520 55.800 56.120 56.400 ;
    END
  END WW4END[3]
  PIN WW4END[4]
    DIRECTION INPUT ;
    USE SIGNAL ;
    ANTENNAGATEAREA 0.972000 ;
    PORT
      LAYER met3 ;
        RECT 55.520 57.160 56.120 57.760 ;
    END
  END WW4END[4]
  PIN WW4END[5]
    DIRECTION INPUT ;
    USE SIGNAL ;
    ANTENNAGATEAREA 0.972000 ;
    PORT
      LAYER met3 ;
        RECT 55.520 58.520 56.120 59.120 ;
    END
  END WW4END[5]
  PIN WW4END[6]
    DIRECTION INPUT ;
    USE SIGNAL ;
    ANTENNAGATEAREA 0.477000 ;
    PORT
      LAYER met3 ;
        RECT 55.520 59.880 56.120 60.480 ;
    END
  END WW4END[6]
  PIN WW4END[7]
    DIRECTION INPUT ;
    USE SIGNAL ;
    ANTENNAGATEAREA 0.477000 ;
    PORT
      LAYER met3 ;
        RECT 55.520 61.240 56.120 61.840 ;
    END
  END WW4END[7]
  PIN WW4END[8]
    DIRECTION INPUT ;
    USE SIGNAL ;
    ANTENNAGATEAREA 0.477000 ;
    PORT
      LAYER met3 ;
        RECT 55.520 62.600 56.120 63.200 ;
    END
  END WW4END[8]
  PIN WW4END[9]
    DIRECTION INPUT ;
    USE SIGNAL ;
    ANTENNAGATEAREA 0.477000 ;
    PORT
      LAYER met3 ;
        RECT 55.520 63.960 56.120 64.560 ;
    END
  END WW4END[9]
  OBS
      LAYER nwell ;
        RECT 2.570 2.635 53.550 220.405 ;
      LAYER li1 ;
        RECT 2.760 2.635 53.360 220.405 ;
      LAYER met1 ;
        RECT 0.530 2.480 55.590 220.960 ;
      LAYER met2 ;
        RECT 0.160 222.480 2.570 222.770 ;
        RECT 3.410 222.480 4.410 222.770 ;
        RECT 5.250 222.480 6.250 222.770 ;
        RECT 7.090 222.480 8.090 222.770 ;
        RECT 8.930 222.480 9.930 222.770 ;
        RECT 10.770 222.480 11.770 222.770 ;
        RECT 12.610 222.480 13.610 222.770 ;
        RECT 14.450 222.480 15.450 222.770 ;
        RECT 16.290 222.480 17.290 222.770 ;
        RECT 18.130 222.480 19.130 222.770 ;
        RECT 19.970 222.480 20.970 222.770 ;
        RECT 21.810 222.480 22.810 222.770 ;
        RECT 23.650 222.480 24.650 222.770 ;
        RECT 25.490 222.480 26.490 222.770 ;
        RECT 27.330 222.480 28.330 222.770 ;
        RECT 29.170 222.480 30.170 222.770 ;
        RECT 31.010 222.480 32.010 222.770 ;
        RECT 32.850 222.480 33.850 222.770 ;
        RECT 34.690 222.480 35.690 222.770 ;
        RECT 36.530 222.480 37.530 222.770 ;
        RECT 38.370 222.480 39.370 222.770 ;
        RECT 40.210 222.480 41.210 222.770 ;
        RECT 42.050 222.480 43.050 222.770 ;
        RECT 43.890 222.480 44.890 222.770 ;
        RECT 45.730 222.480 46.730 222.770 ;
        RECT 47.570 222.480 48.570 222.770 ;
        RECT 49.410 222.480 50.410 222.770 ;
        RECT 51.250 222.480 52.250 222.770 ;
        RECT 53.090 222.480 55.960 222.770 ;
        RECT 0.160 0.560 55.960 222.480 ;
        RECT 0.160 0.270 2.570 0.560 ;
        RECT 3.410 0.270 4.410 0.560 ;
        RECT 5.250 0.270 6.250 0.560 ;
        RECT 7.090 0.270 8.090 0.560 ;
        RECT 8.930 0.270 9.930 0.560 ;
        RECT 10.770 0.270 11.770 0.560 ;
        RECT 12.610 0.270 13.610 0.560 ;
        RECT 14.450 0.270 15.450 0.560 ;
        RECT 16.290 0.270 17.290 0.560 ;
        RECT 18.130 0.270 19.130 0.560 ;
        RECT 19.970 0.270 20.970 0.560 ;
        RECT 21.810 0.270 22.810 0.560 ;
        RECT 23.650 0.270 24.650 0.560 ;
        RECT 25.490 0.270 26.490 0.560 ;
        RECT 27.330 0.270 28.330 0.560 ;
        RECT 29.170 0.270 30.170 0.560 ;
        RECT 31.010 0.270 32.010 0.560 ;
        RECT 32.850 0.270 33.850 0.560 ;
        RECT 34.690 0.270 35.690 0.560 ;
        RECT 36.530 0.270 37.530 0.560 ;
        RECT 38.370 0.270 39.370 0.560 ;
        RECT 40.210 0.270 41.210 0.560 ;
        RECT 42.050 0.270 43.050 0.560 ;
        RECT 43.890 0.270 44.890 0.560 ;
        RECT 45.730 0.270 46.730 0.560 ;
        RECT 47.570 0.270 48.570 0.560 ;
        RECT 49.410 0.270 50.410 0.560 ;
        RECT 51.250 0.270 52.250 0.560 ;
        RECT 53.090 0.270 55.960 0.560 ;
      LAYER met3 ;
        RECT 0.600 211.840 55.520 220.485 ;
        RECT 1.000 210.440 55.520 211.840 ;
        RECT 0.600 206.400 55.520 210.440 ;
        RECT 1.000 205.000 55.520 206.400 ;
        RECT 0.600 200.960 55.520 205.000 ;
        RECT 1.000 199.560 55.520 200.960 ;
        RECT 0.600 198.240 55.520 199.560 ;
        RECT 0.600 195.520 55.120 198.240 ;
        RECT 1.000 194.120 55.120 195.520 ;
        RECT 0.600 190.080 55.120 194.120 ;
        RECT 1.000 188.680 55.120 190.080 ;
        RECT 0.600 184.640 55.120 188.680 ;
        RECT 1.000 183.240 55.120 184.640 ;
        RECT 0.600 179.200 55.120 183.240 ;
        RECT 1.000 177.800 55.120 179.200 ;
        RECT 0.600 173.760 55.120 177.800 ;
        RECT 1.000 172.360 55.120 173.760 ;
        RECT 0.600 168.320 55.120 172.360 ;
        RECT 1.000 166.920 55.120 168.320 ;
        RECT 0.600 162.880 55.120 166.920 ;
        RECT 1.000 161.480 55.120 162.880 ;
        RECT 0.600 157.440 55.120 161.480 ;
        RECT 1.000 156.040 55.120 157.440 ;
        RECT 0.600 152.000 55.120 156.040 ;
        RECT 1.000 150.600 55.120 152.000 ;
        RECT 0.600 146.560 55.120 150.600 ;
        RECT 1.000 145.160 55.120 146.560 ;
        RECT 0.600 141.120 55.120 145.160 ;
        RECT 1.000 139.720 55.120 141.120 ;
        RECT 0.600 135.680 55.120 139.720 ;
        RECT 1.000 134.280 55.120 135.680 ;
        RECT 0.600 130.240 55.120 134.280 ;
        RECT 1.000 128.840 55.120 130.240 ;
        RECT 0.600 124.800 55.120 128.840 ;
        RECT 1.000 123.400 55.120 124.800 ;
        RECT 0.600 119.360 55.120 123.400 ;
        RECT 1.000 117.960 55.120 119.360 ;
        RECT 0.600 113.920 55.120 117.960 ;
        RECT 1.000 112.520 55.120 113.920 ;
        RECT 0.600 108.480 55.120 112.520 ;
        RECT 1.000 107.080 55.120 108.480 ;
        RECT 0.600 103.040 55.120 107.080 ;
        RECT 1.000 101.640 55.120 103.040 ;
        RECT 0.600 97.600 55.120 101.640 ;
        RECT 1.000 96.200 55.120 97.600 ;
        RECT 0.600 92.160 55.120 96.200 ;
        RECT 1.000 90.760 55.120 92.160 ;
        RECT 0.600 86.720 55.120 90.760 ;
        RECT 1.000 85.320 55.120 86.720 ;
        RECT 0.600 81.280 55.120 85.320 ;
        RECT 1.000 79.880 55.120 81.280 ;
        RECT 0.600 75.840 55.120 79.880 ;
        RECT 1.000 74.440 55.120 75.840 ;
        RECT 0.600 70.400 55.120 74.440 ;
        RECT 1.000 69.000 55.120 70.400 ;
        RECT 0.600 64.960 55.120 69.000 ;
        RECT 1.000 63.560 55.120 64.960 ;
        RECT 0.600 59.520 55.120 63.560 ;
        RECT 1.000 58.120 55.120 59.520 ;
        RECT 0.600 54.080 55.120 58.120 ;
        RECT 1.000 52.680 55.120 54.080 ;
        RECT 0.600 48.640 55.120 52.680 ;
        RECT 1.000 47.240 55.120 48.640 ;
        RECT 0.600 43.200 55.120 47.240 ;
        RECT 1.000 41.800 55.120 43.200 ;
        RECT 0.600 37.760 55.120 41.800 ;
        RECT 1.000 36.360 55.120 37.760 ;
        RECT 0.600 32.320 55.120 36.360 ;
        RECT 1.000 30.920 55.120 32.320 ;
        RECT 0.600 26.880 55.120 30.920 ;
        RECT 1.000 25.480 55.120 26.880 ;
        RECT 0.600 24.120 55.120 25.480 ;
        RECT 0.600 21.440 55.520 24.120 ;
        RECT 1.000 20.040 55.520 21.440 ;
        RECT 0.600 16.000 55.520 20.040 ;
        RECT 1.000 14.600 55.520 16.000 ;
        RECT 0.600 10.560 55.520 14.600 ;
        RECT 1.000 9.160 55.520 10.560 ;
        RECT 0.600 2.555 55.520 9.160 ;
      LAYER met4 ;
        RECT 0.310 7.655 6.560 216.745 ;
        RECT 8.960 7.655 11.860 216.745 ;
        RECT 14.260 7.655 36.560 216.745 ;
        RECT 38.960 7.655 41.860 216.745 ;
        RECT 44.260 7.655 55.810 216.745 ;
  END
END W_IO2
END LIBRARY

